One B-rep face of a CAD part: STEP entity #518.
In plain terms, the planar face has unit normal (0, -1, 0).
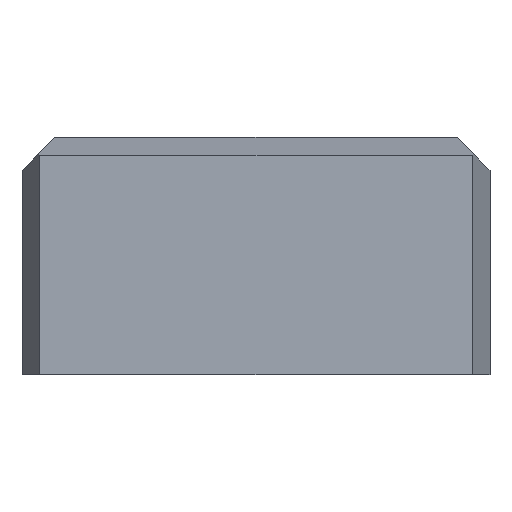
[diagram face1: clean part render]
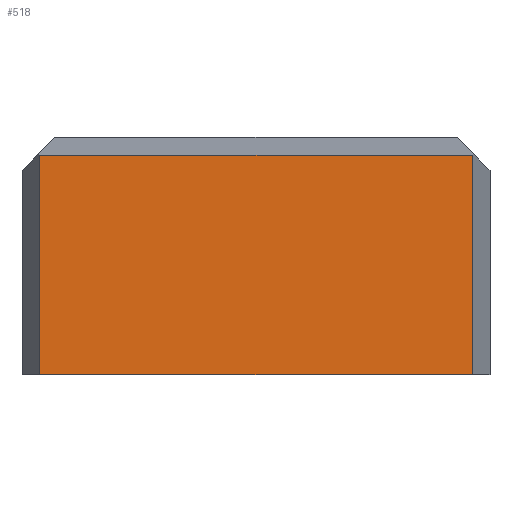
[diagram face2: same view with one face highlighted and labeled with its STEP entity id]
Its self-contained STEP definition (entity closure, numbers rounded to 3 decimals):
#98=CARTESIAN_POINT('Vertex',(32.821,0.,-36.)) ;
#101=CARTESIAN_POINT('Line Origine',(0.,0.,-36.)) ;
#105=CARTESIAN_POINT('Vertex',(-32.821,0.,-36.)) ;
#479=CARTESIAN_POINT('Vertex',(32.821,0.,-2.679)) ;
#482=CARTESIAN_POINT('Line Origine',(32.821,0.,-19.34)) ;
#495=CARTESIAN_POINT('Axis2P3D Location',(-32.821,0.,-36.)) ;
#500=CARTESIAN_POINT('Line Origine',(0.,0.,-2.679)) ;
#504=CARTESIAN_POINT('Vertex',(-32.821,0.,-2.679)) ;
#507=CARTESIAN_POINT('Line Origine',(-32.821,0.,-19.34)) ;
#102=DIRECTION('Vector Direction',(1.,0.,0.)) ;
#483=DIRECTION('Vector Direction',(0.,0.,1.)) ;
#496=DIRECTION('Axis2P3D Direction',(0.,-1.,0.)) ;
#497=DIRECTION('Axis2P3D XDirection',(0.,0.,-1.)) ;
#501=DIRECTION('Vector Direction',(-1.,0.,0.)) ;
#508=DIRECTION('Vector Direction',(0.,0.,1.)) ;
#498=AXIS2_PLACEMENT_3D('Plane Axis2P3D',#495,#496,#497) ;
#513=ORIENTED_EDGE('',*,*,#486,.T.) ;
#514=ORIENTED_EDGE('',*,*,#506,.T.) ;
#515=ORIENTED_EDGE('',*,*,#511,.F.) ;
#516=ORIENTED_EDGE('',*,*,#107,.T.) ;
#103=VECTOR('Line Direction',#102,1.) ;
#484=VECTOR('Line Direction',#483,1.) ;
#502=VECTOR('Line Direction',#501,1.) ;
#509=VECTOR('Line Direction',#508,1.) ;
#518=ADVANCED_FACE('A927-71X180X36',(#517),#499,.T.) ;
#107=EDGE_CURVE('',#106,#99,#104,.T.) ;
#486=EDGE_CURVE('',#99,#480,#485,.T.) ;
#506=EDGE_CURVE('',#480,#505,#503,.T.) ;
#511=EDGE_CURVE('',#106,#505,#510,.T.) ;
#512=EDGE_LOOP('',(#513,#514,#515,#516)) ;
#517=FACE_OUTER_BOUND('',#512,.T.) ;
#104=LINE('Line',#101,#103) ;
#485=LINE('Line',#482,#484) ;
#503=LINE('Line',#500,#502) ;
#510=LINE('Line',#507,#509) ;
#499=PLANE('Plane',#498) ;
#99=VERTEX_POINT('',#98) ;
#106=VERTEX_POINT('',#105) ;
#480=VERTEX_POINT('',#479) ;
#505=VERTEX_POINT('',#504) ;
